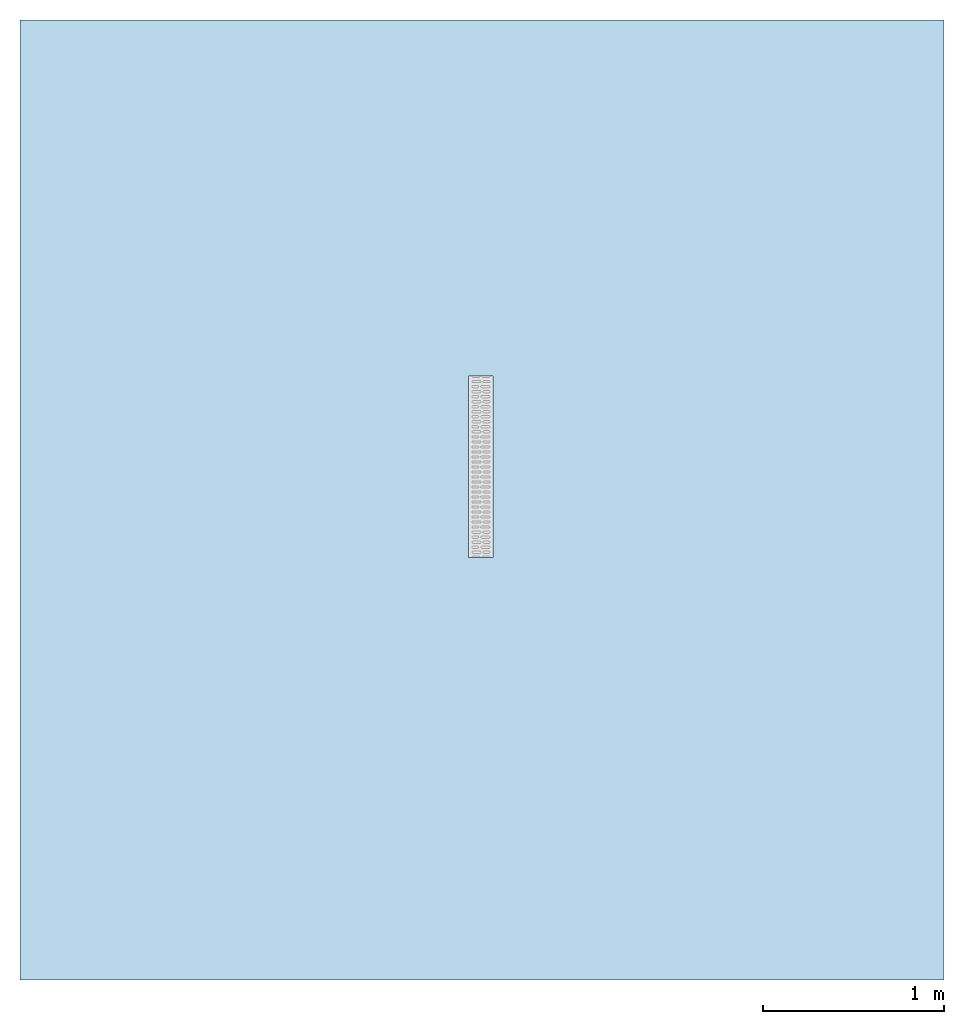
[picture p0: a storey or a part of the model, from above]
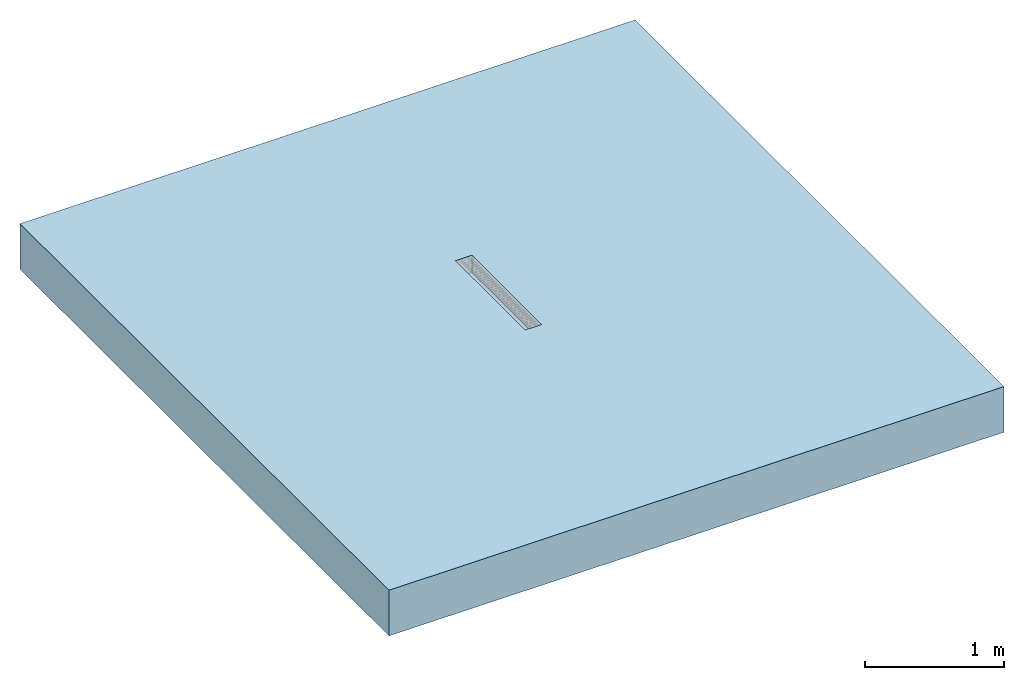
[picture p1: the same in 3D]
Properties of the parts of a building model (IFC2X3)

# File
Description: ViewDefinition [CoordinationView]
File name: 23000 - No 0.0 Constant Depth Channel - 1000mm LG - Invert Depth 130mm.ifc
Time: 2013-10-16T12:02:07
Written by: Autodesk Revit 2013
Made in: 20120221_2030(x64)

# IfcProject, Project Number
LongName: Project Name; Phase: Project Status

# IfcSite, Default
RefLatitude: 42, 21, 30, 344238; RefLongitude: -71, -3, -35, -194702; RefElevation: 0 mm

# IfcBuilding
Pset_BuildingCommon - NumberOfStoreys: 1
Other - Project Number: Project Number; Client Name: Owner; Project Name: Project Name; Project Status: Project Status; Project Issue Date: Issue Date; Project Address: ## Street City, State Zip

# IfcBuildingStorey, Level 1
LongName: Level 1; Elevation: 0 mm
Constraints - Elevation Base: 0; Elevation: 0 mm
Graphics - Symbol: M_Level Head - Circle: M_Level Head - Circle; Line Weight: 1; Symbol at End 2 Default: yes; Line Pattern: Center; Color: 0; Symbol at End 1 Default: no
Identity Data - Structural: no; Building Story: yes; Name: Level 1
Dimensions - Computation Height: 0 mm

# IfcBuildingElementProxy: 23000 - No 0.0 Constant Depth Channel - 1000mm LG - Invert Depth 130mm, Civil-Drainage-Channel-ACO-MultiDrain-M100D-Channel-System:23000 - No 0.0 Constant Depth Channel - 1000mm LG - Invert Depth 130mm:23000 - No 0.0 Constant Depth Channel - 1000mm LG - Invert Depth 130mm:1089344
In: Level 1
Material: Vienite® Synthetic Resin Concrete
Constraints - Moves With Nearby Elements: no; Level: Level: Level 1
Dimensions - Length: 1000 mm; FloorCut_Length: -1000 mm; EndCap Position: 1000 mm; Volume: 9515982 mm3; Custom_Value_Length: 0 mm; FloorCut_Width: 135 mm; InvDepth: 80 mm; ShallowOverallDepth: 75 mm; Length Drain: -1000 mm; SlopingOverallDepth: 245 mm; FloorCut_HorPosition: 67.5 mm; EndCap_Height: 150 mm; SlopingInvertDepth: 175 mm; ShallowInvDepth: 55 mm; EndCap_Female_Height: 150 mm; SlopingEndInvertDepth: 180 mm; SlopingEndOverallDepth: 250 mm; Endcap_Void_Depth: 0 mm; Depth: 150 mm; FloorCut_Depth: 150 mm
Construction - 12614 - Grating - Slotted - Galvanised Steel - 1000mm Long: no; 23405 - Grating - Heelguard™ - Ductile Iron - 500mm Long: no; 12656 - Grating - Perforated - Galvanised Steel - 1000mm long: no; 12619 - Grating - Mesh - Galvanised Steel - 500mm Long: no; 23408 - Grating - Slotted - Ductile Iron - 500mm Long: no; 12611 - Grating - Slotted - Galvanised Steel - 500mm Long: no; 12673 - Grating - Intercept - Ductile Iron - 500mm Long: no; 12666 - Grating - Perforated - Galvanised Steel - 1000mm Long: no; 12615 - Grating - Slotted - Galvanised Steel - 500mm Long: no; 23406 - Grating - Solid Cover - Ductile Iron - 500mm Long: no; 12657 - Grating - Perforated - Galvanised Steel - 500mm long: no; 23409 - Grating - ATec coated - Heelguard™ - Ductile Iron - 500mm Long: no; 12610 - Grating - Slotted - Galvanised Steel - 1000mm Long: no; 12680 - Grating - Heelguard™ - Composite Black - 500mm Long: no; 12618 - Grating - Mesh - Galvanised Steel - 1000mm Long: no; 23404 - Universal Endcap - Male End: no; 23404 - Universal Endcap - Female End: no; 12667 - Grating - Perforated - Galvanised Steel - 500mm Long: no; 23452 - Kerb Outlet Half Batter: no; 23453 - Kerb Outlet Bull Nose: no; 23450 - Downpipe connector 75mm Depth: no; Sloping Channel: no; Shallow Depth Channel: no; Shallow Depth Channel with seal: no; Constant Depth Junction Channel: no; Sump Unit: no; Constant Depth Channel: yes; 23451 - Downpipe connector 100mm Depth: no; Grating 1000mm: yes
Phasing - Phase Created: New Construction
Pset_BuildingElementProxyCommon - Reference: 23000 - No 0.0 Constant Depth Channel - 1000mm LG - Invert Depth 130mm
Identity Data - Price: POA - contact ACO; Assembly Code: D2040; Model Description: Channel drainage system; Cost: 0; URL: www.aco.co.uk; Watermark 2: This file is watermarked and users are prohibited to reproduce, adapt, distribute this information; Watermarked With: BIM Manager Premium Suite; Product brochure: http://www.aco.co.uk/download.php?id=173; Installation guidelines: http://www.aco.co.uk/download.php?id=173; Maintenance guidelines: http://www.aco.co.uk/download.php?id=173; Watermark 1: This file is the property of ACO Technologies PLC; Telephone: +44 (0)1462 816666; Product Code: 23000; Type Comments: ACO MultiDrain M100D 0.0 Constant Depth Channel 1000mm Long; Address: ACO Business Park, Hitchin Road, Shefford, Bedfordshire, United Kingdom SG17 5TE; Manufacturer: ACO Technologies plc - ACO Water Management Division; Watermarked By: www.aco.co.uk; Assembly Description: Rain Water Drainage; OmniClass Title: Rainwater Removal; OmniClass Number: 23.70.50.24; e-mail Technical: technical@aco.co.uk; Product Page URL: http://www.aco.co.uk/product_detail.php?id=15; Model: ACO MultiDrain MD - M100D; Fax: +44 (0)1462 815895; e-mail Sales: customersupport@aco.co.uk
General - TagNumber: 0; SerialNumber: 0
Green Building Properties - Channel Recycled Material Content: 20% minimum; Channel Recyclable: Fully recyclable; Edge Rail Recycled Material Content: Between 40% - 90%; Edge Rail Recyclable: Fully recyclable
Model Properties - Grating Product code 12619: Load Class C250 - Meshed Steel 412DL 500mm long- 25x12mm slot - Intake Area 88000mm²/m - 1.5kg; Grating Product code 23408: Load Class D400 - Intercept Ductile Iron 507DL - 500mm long - 12mm slot - Intake Area 36200mm²/m - 3.8kg; Grating Product code 23409: Load Class D400 - ATec coated Heelguard Ductile Iron 23409DL - 500mm long - 8mm slot - Intake Area 25400mm²/m - 4.2kg; End Cap Product code 23404: No. 306 Universal End Cap - 135mm wide x 300mm long - Spigot Ø110mm x 50mm long - Silver - Polypropylene - 0.16kg; Grating Product code 12610: Load Class A15 - Slotted Galvanised Steel 400DL - 1000mm long - 10mm slot - Intake Area 31200mm²/m - 2.2kg; Grating Product code 12611: Load Class A15 - Slotted Galvanised Steel 402DL - 500mm long - 10mm slot - Intake Area 31200mm²/m - 1kg; Grating Product code 12615: Load Class C250 - Slotted Galvanised Steel 424DL 500mm long- 10mm slot - Intake Area 31200mm²/m - 2.2kg; Grating Product code 23405: Load Class D400 - Heelguard Ductile Iron 23405DL - 500mm long - 8mm slot - Intake Area 25400mm²/m - 4.2kg; Grating Product code 12656: Load Class C250 - Perforated Galvanised Steel 12656DL 1000mm long - 6mm hole - Intake Area 17800mm²/m - 4.8kg Load Class C250 - Perforated Galvanised Steel 12657DL 500mm long, 2.4kg; Grating Product code 12673: Load Class C250 - Intercept Ductile Iron 507DL - 500mm long - 31x12mm slot - Intake Area 43000mm²/m - 3.5kg; Grating Product code 12667: Load Class A15 - Perforated Galvanised Steel 12667DL - 500mm long - 6mm hole - Intake Area 17800mm²/m - 1kg Load Class C250 - Heelguard Composite Black 522DL - 500mm long - 1.2kg; Grating Product code 12614: Load Class C250 - Slotted Galvanised Steel 423DL 1000mm long- 10mm slot - Intake Area 31200mm²/m - 4.3kg; Grating Product code 12618: Load Class C250 - Meshed Galvanised Steel 410DL 1000mm long - 25x12mm slot - Intake Area 88000mm²/m - 3.1kg; Grating Product code 12657: Load Class C250 - Perforated Galvanised Steel 12657DL 500mm long- 6mm hole - Intake Area 17800mm²/m - 2.4kg; Grating Product code 12680: Load Class C250 - Heelguard Composite Black 522DL - 500mm long - 8mm slot - Intake Area 14250mm²/m - 1.2kg; Grating Product code 23406: Load Class D400 - Solid Cover Ductile Iron 23406DL - 500mm long - 4.5kg; Grating Product code 12666: Load Class A15 - Perforated Galvanised Steel 12666DL - 1000mm long - 6mm hole - Intake Area 17800mm²/m - 2.2kg
Data - Hydraulic Performance: http://www.aco.co.uk/download.php?id=173; Invert Depth: 130mm; Concrete Surround Volume - Load Class D 400 - Concrete Pavement: 0.17m³/m; Channel C.S.A: 0.0059m²; Load Class: A 15 - D 400; Product Standard: BS EN 1433:2002, CE marked; Product Weight: 11 Kg; Pre-formed Outlet Ø: N/A; Installation - Concrete Grade: Refer to brochure; Concrete Surround Volume - Load Class B 125 - C 250 - Concrete Pavement: 0.11m³/m; Concrete Surround Volume - Load Class A 15 - Concrete Pavement: 0.07m³/m; Product Dimensions: 1000mm x 135mm x 100mm (LxWxH); ACO Hydraulic Design Software: http://www.acodesign.co.uk
Other - CreatedBy: www.aco.co.uk; Revision: 1
Materials and Finishes - Edge Rail Finish: Pre-galvanised; Channel Material: Vienite® Synthetic Resin Concrete; Channel Colour: Brown; Edge Rail Colour: Silver; Edge Rail Material: Steel

# IfcOpeningElement: Recess
In: Level 1
Constraints - Level: Level: Level 1; Related to Mass: no; Height Offset From Level: 0 mm; Room Bounding: yes
Structural - Structural: no; Enable Analytical Model: no
Dimensions - Thickness: 400 mm; Volume: 10791750000 mm3; Area: 27030000 mm2; Perimeter: 20800 mm
Phasing - Phase Created: New Construction
Materials and Finishes - Structural Material: Plant
Analytical Properties - Absorptance: 0.1; Roughness: 1
Construction - Default Thickness: 400 mm; Function: 0
Graphics - Coarse Scale Fill Color: 0

# IfcSlab: Floor:Generic Floor - 400mm, Floor:Generic Floor - 400mm:193825
In: Level 1
PredefinedType: FLOOR; Material: Plant 400 mm
Constraints - Level: Level: Level 1; Related to Mass: no; Height Offset From Level: 0 mm; Room Bounding: yes
Structural - Structural: no; Enable Analytical Model: no
Dimensions - Thickness: 400 mm; Volume: 10791750000 mm3; Area: 27030000 mm2; Perimeter: 20800 mm
Phasing - Phase Created: New Construction
Pset_SlabCommon - Reference: Generic Floor - 400mm; IsExternal: no; LoadBearing: yes
Materials and Finishes - Structural Material: Plant
Analytical Properties - Absorptance: 0.1; Roughness: 1
Construction - Default Thickness: 400 mm; Function: 0
Graphics - Coarse Scale Fill Color: 0
